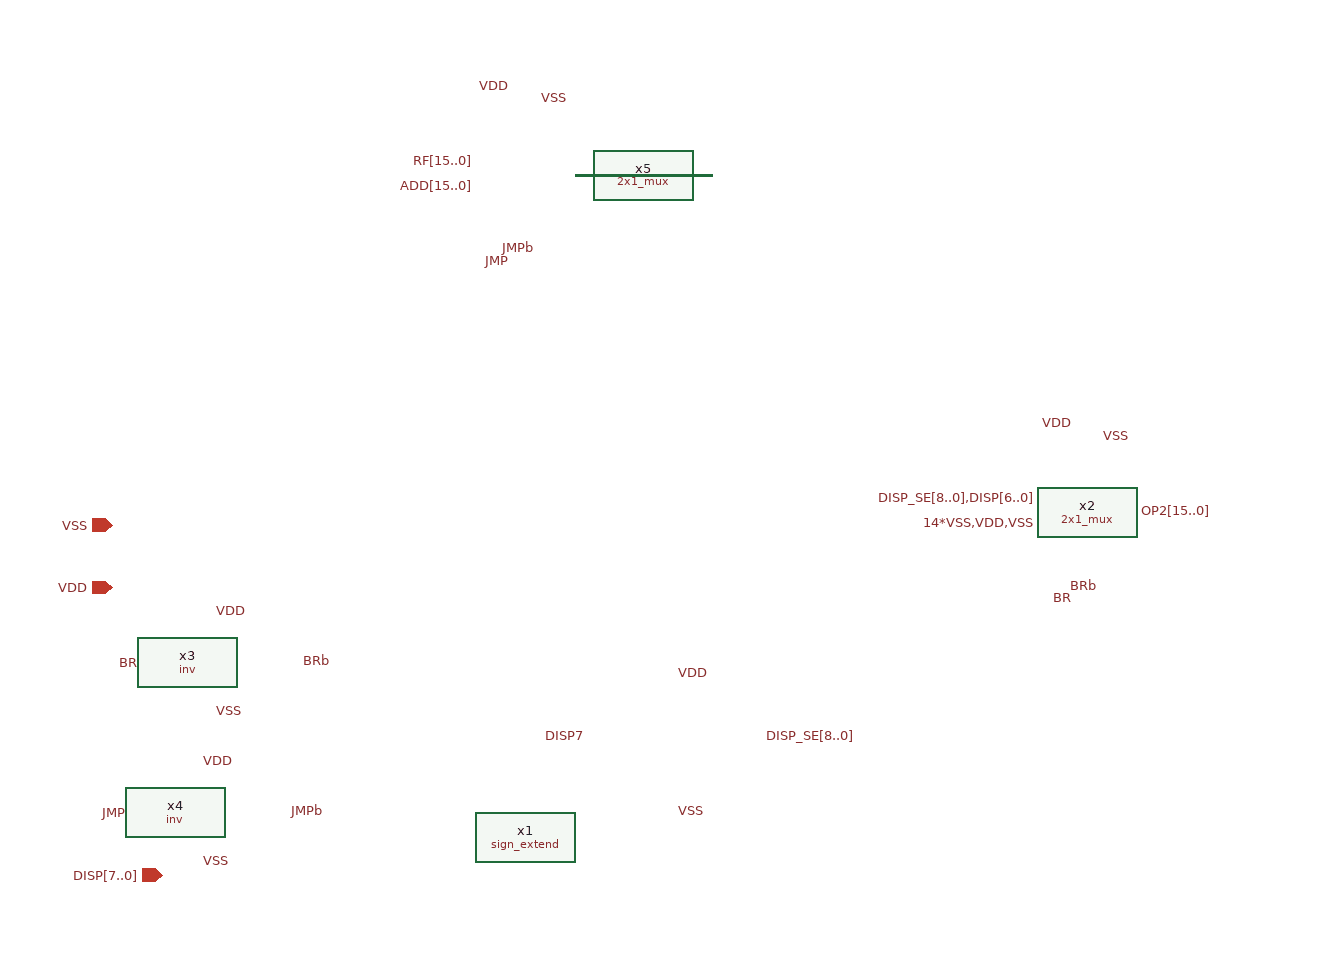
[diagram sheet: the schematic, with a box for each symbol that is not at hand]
v {xschem version=3.4.7 file_version=1.2}
G {}
K {}
V {}
S {}
E {}
N 390 -580 500 -580 {lab=#net1
bus=true}
C {ipin.sym} 50 -70 0 0 {name=p1 lab=JMP}
C {ipin.sym} 60 -190 0 0 {name=p3 lab=BR}
C {iopin.sym} 20 -250 0 0 {name=p4 lab=VDD}
C {iopin.sym} 20 -300 0 0 {name=p5 lab=VSS}
C {ipin.sym} 60 -20 0 0 {name=p6 lab=DISP[7..0]}
C {engn1600-team1/CAD6/sign_extend.sym} 350 -50 0 0 {name=x1}
C {lab_pin.sym} 470 -180 0 1 {name=p7 lab=VDD}
C {lab_pin.sym} 470 -70 0 1 {name=p8 lab=VSS}
C {lab_pin.sym} 540 -130 0 1 {name=p9 lab=DISP_SE[8..0]}
C {lab_pin.sym} 400 -130 0 0 {name=p10 lab=DISP7}
C {lab_pin.sym} 760 -320 0 0 {name=p2 lab=DISP_SE[8..0],DISP[6..0]}
C {engn1600-team1/CAD6/2x1_mux.sym} 800 -310 0 0 {name=x2}
C {engn1600-team1/CAD6/inv.sym} 80 -190 0 0 {name=x3 kINV=1}
C {lab_pin.sym} 100 -230 0 1 {name=p11 lab=VDD}
C {lab_pin.sym} 170 -190 0 1 {name=p12 lab=BRb}
C {lab_pin.sym} 100 -150 0 1 {name=p13 lab=VSS}
C {lab_pin.sym} 790 -240 0 0 {name=p14 lab=BR}
C {lab_pin.sym} 810 -250 0 0 {name=p15 lab=BRb}
C {lab_pin.sym} 840 -310 0 1 {name=p16 lab=OP2[15..0]}
C {lab_pin.sym} 790 -380 0 0 {name=p17 lab=VDD}
C {lab_pin.sym} 810 -370 0 1 {name=p18 lab=VSS}
C {lab_pin.sym} 760 -300 0 0 {name=p19 lab=14*VSS,VDD,VSS}
C {engn1600-team1/CAD6/inv.sym} 70 -70 0 0 {name=x4 kINV=1}
C {lab_pin.sym} 90 -110 0 1 {name=p20 lab=VDD}
C {lab_pin.sym} 160 -70 0 1 {name=p21 lab=JMPb}
C {lab_pin.sym} 90 -30 0 1 {name=p22 lab=VSS}
C {engn1600-team1/CAD6/2x1_mux.sym} 350 -580 0 0 {name=x5}
C {lab_pin.sym} 310 -590 0 0 {name=p23 lab=RF[15..0]}
C {lab_pin.sym} 340 -510 0 0 {name=p24 lab=JMP}
C {lab_pin.sym} 360 -520 0 0 {name=p25 lab=JMPb}
C {lab_pin.sym} 340 -650 0 0 {name=p27 lab=VDD}
C {lab_pin.sym} 360 -640 0 1 {name=p28 lab=VSS}
C {lab_pin.sym} 310 -570 0 0 {name=p29 lab=ADD[15..0]}
